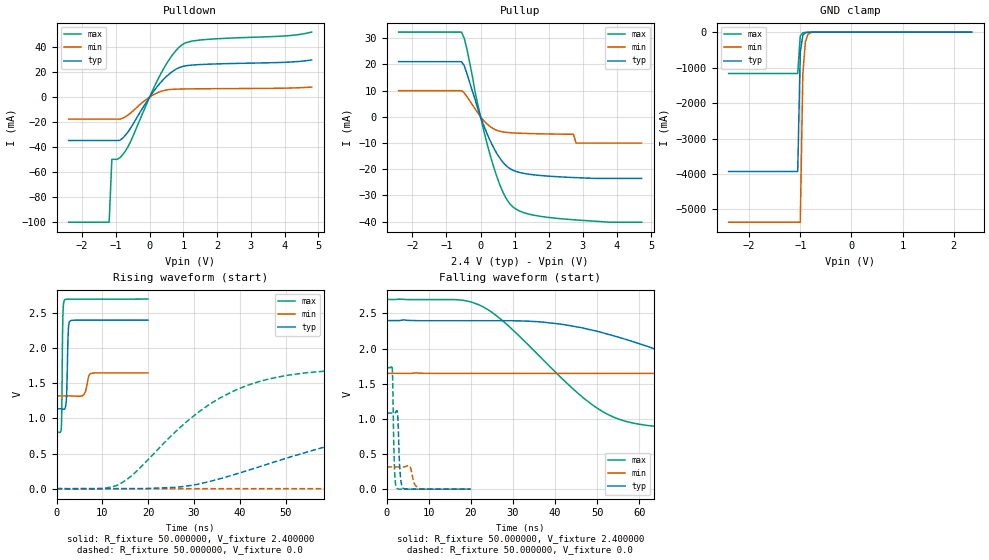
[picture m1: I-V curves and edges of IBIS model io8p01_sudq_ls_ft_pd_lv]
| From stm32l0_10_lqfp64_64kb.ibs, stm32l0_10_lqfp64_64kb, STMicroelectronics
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|   Model io8p01_sudq_ls_ft_pd_lv
[Model]  io8p01_sudq_ls_ft_pd_lv
Model_type I/O
Polarity   Non-Inverting
Enable   Active-Low
Vinl =   0.720000V
Vinh =   1.680000V
Vmeas =  1.200000V
Cref =   50.000000pF
Rref =   100.000000M
Vref =   0.0V
C_comp   2.317700pF   2.286600pF   2.332700pF
[Temperature Range]   25.000000   0.105000k   -40.000000
[Pullup Reference]   2.400000V   1.650000V   2.700000V
[Pulldown Reference]   0.0V   0.0V   0.0V
[POWER Clamp Reference]   2.400000V   1.650000V   2.700000V
[GND Clamp Reference]   0.0V   0.0V   0.0V
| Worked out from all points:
|   slope of the pulldown table from 0 to 0.36 V, typ, clamps not added: 28.4 ohm
|   slope of the pullup table from 0 to 0.36 V, typ, clamps not added: 32.2 ohm
|   GND clamp passes 1 mA (typ) near -0.64 V on its own axis
|   rising waveform, R_fixture 50.000000, V_fixture 2.400000: 20-80 % time 276ps typ, 630ps min, 184ps max; typ from 1.14 V to 2.4 V
|   rising waveform, R_fixture 50.000000, V_fixture 0.0: 20-80 % time 39.8ns typ, 107ns min, 19.5ns max; typ from 0 V to 1.08 V
|   falling waveform, R_fixture 50.000000, V_fixture 2.400000: 20-80 % time 41.2ns typ, 107ns min, 20.3ns max; typ from 2.4 V to 1.14 V
|   falling waveform, R_fixture 50.000000, V_fixture 0.0: 20-80 % time 453ps typ, 828ps min, 354ps max; typ from 1.08 V to 0 V
[Pulldown]
|Voltage   I(typ)   I(min)   I(max)
-2.4V     -34.71mA   -17.62mA   -100mA
-1.2V     -34.71mA   -17.62mA   -100mA
-1.12V    -34.71mA   -17.62mA   -49.77mA
-960mV    -34.71mA   -17.62mA   -49.77mA
-720mV    -30.52mA   -15.81mA   -43.23mA
-560mV    -24.66mA   -12.69mA   -35.3mA
-80mV     -3.3mA     -1.497mA   -4.982mA
320mV     11.47mA    4.39mA     18.08mA
640mV     19.72mA    6.139mA    32.34mA
960mV     24.33mA    6.432mA    41.77mA
1.52V     26.01mA    6.612mA    45.64mA
4.8V      29.64mA    7.944mA    51.92mA
[Pullup]
|Voltage   I(typ)   I(min)   I(max)
-2.4V     21.06mA    9.987mA    32.34mA
-560mV    21.06mA    9.987mA    32.34mA
-480mV    19.56mA    9.181mA    30.05mA
-400mV    16.53mA    7.734mA    25.89mA
-80mV     3.011mA    1.498mA    4.671mA
320mV     -10.16mA   -4.078mA   -16.34mA
640mV     -17.08mA   -5.718mA   -28.28mA
960mV     -20.45mA   -6.129mA   -34.5mA
2V        -22.64mA   -6.529mA   -38.4mA
2.72V     -23.16mA   -6.64mA    -39.27mA
2.8V      -23.2mA    -10mA      -39.35mA
4.72V     -23.5mA    -10mA      -40.2mA
[GND_clamp]
|Voltage   I(typ)   I(min)   I(max)
-2.4V     -3.929A    -5.359A    -1.166A
-1.05V    -3.929A    -5.359A    -1.166A
-1V       -574.5mA   -5.359A    -109.1mA
-950mV    -90.03mA   -1.192A    -18.56mA
-900mV    -18.42mA   -269.7mA   -9.058mA
-850mV    -6.777mA   -63.61mA   -6.588mA
-800mV    -4.039mA   -16.67mA   -4.867mA
-650mV    -1.055mA   -1.235mA   -1.154mA
2.35V     52.69uA    50.02uA    36.84uA
[POWER_clamp]
|Voltage   I(typ)   I(min)   I(max)
-2.4V     0A         0A         0A
0V        0A         0A         0A
[Ramp]
| variable   typ   min   max
dV/dt_r  0.65004/39.76015n   0.18950/0.10689u   1.03746/19.42297n
dV/dt_f  0.75708/41.15289n   0.19506/0.10670u   1.13772/20.24690n
R_load = 50.000000
[Rising Waveform]
R_fixture= 50.000000
V_fixture= 2.400000
V_fixture_min= 1.650000
V_fixture_max= 2.700000
|time   V(typ)   V(min)   V(max)
0s        1.137V     1.32V      803.3mV
1.041ns   1.137V     1.32V      870.1mV
1.161ns   1.136V     1.32V      1.186V
1.361ns   1.133V     1.32V      2.385V
1.722ns   1.132V     1.32V      2.685V
2.162ns   1.288V     1.32V      2.697V
2.563ns   2.246V     1.32V      2.697V
2.963ns   2.388V     1.32V      2.698V
7.608ns   2.399V     1.642V     2.698V
19.94ns   2.399V     1.649V     2.7V
[Rising Waveform]
R_fixture= 50.000000
V_fixture= 0.0
V_fixture_min= 0.0
V_fixture_max= 0.0
|time   V(typ)   V(min)   V(max)
0s        1.262nV    6.227nV    1.047nV
14.01ns   -220.5uV   -46.69uV   74.63mV
30.03ns   53.04mV    -46.12uV   1.041V
40.04ns   225.4mV    -45.81uV   1.43V
48.05ns   390.7mV    -38.86uV   1.586V
61.06ns   635.3mV    -10.19uV   1.687V
90.09ns   948mV      1.517mV    1.725V
134.1ns   1.067V     59.43mV    1.729V
256.3ns   1.083V     267mV      1.729V
498.5ns   1.083V     316.1mV    1.729V
[Falling Waveform]
R_fixture= 50.000000
V_fixture= 2.400000
V_fixture_min= 1.650000
V_fixture_max= 2.700000
|time   V(typ)   V(min)   V(max)
0s        2.399V     1.649V     2.7V
22.02ns   2.397V     1.648V     2.622V
37.04ns   2.377V     1.648V     1.849V
52.05ns   2.213V     1.648V     1.078V
59.06ns   2.088V     1.648V     934.2mV
73.07ns   1.798V     1.647V     852.8mV
100.1ns   1.36V      1.647V     815.1mV
138.1ns   1.198V     1.632V     805.1mV
292.3ns   1.138V     1.376V     803.3mV
498.5ns   1.137V     1.32V      803.3mV
[Falling Waveform]
R_fixture= 50.000000
V_fixture= 0.0
V_fixture_min= 0.0
V_fixture_max= 0.0
|time   V(typ)   V(min)   V(max)
0s        1.083V     316.1mV    1.729V
1.361ns   1.083V     316.1mV    1.718V
1.882ns   1.083V     316.1mV    318.6mV
2.442ns   1.117V     316.1mV    15.2mV
2.683ns   1.015V     316.1mV    3.975mV
3.203ns   248mV      315.9mV    146.4uV
3.844ns   17.68mV    315.6mV    -22.31uV
5.445ns   -798.8nV   330.6mV    -26.61uV
7.928ns   -5.539uV   7.752mV    -22.07uV
19.94ns   1.262nV    6.227nV    1.047nV
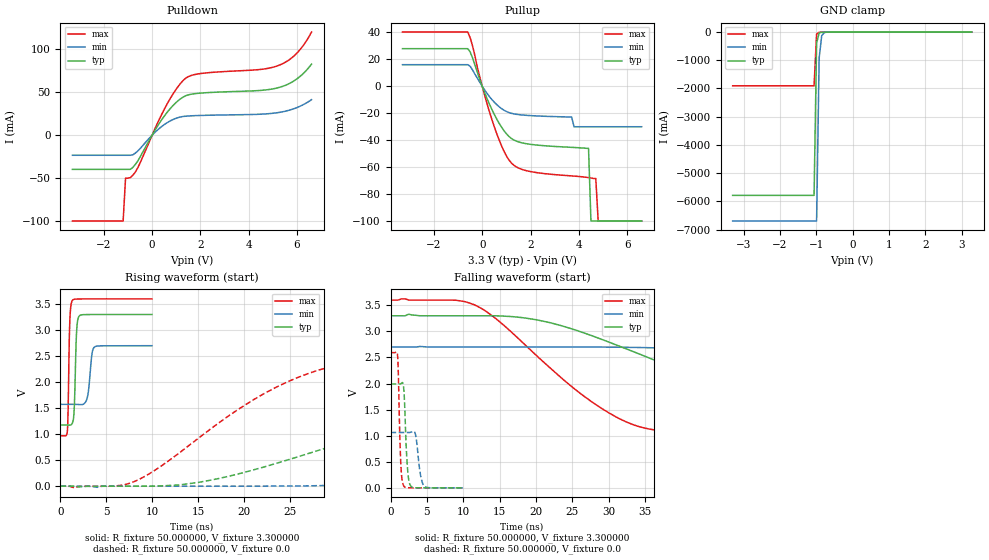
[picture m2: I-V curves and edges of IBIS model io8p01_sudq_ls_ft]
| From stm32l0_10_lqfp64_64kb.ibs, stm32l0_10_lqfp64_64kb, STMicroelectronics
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|   Model io8p01_sudq_ls_ft
[Model]  io8p01_sudq_ls_ft
Model_type I/O
Polarity   Non-Inverting
Enable   Active-Low
Vinl =   0.990000V
Vinh =   2.310000V
Vmeas =  1.650000V
Cref =   50.000000pF
Rref =   100.000000M
Vref =   0.0V
C_comp   2.343000pF   2.309800pF   2.393900pF
[Temperature Range]   25.000000   0.125000k   -40.000000
[Pullup Reference]   3.300000V   2.700000V   3.600000V
[Pulldown Reference]   0.0V   0.0V   0.0V
[POWER Clamp Reference]   3.300000V   2.700000V   3.600000V
[GND Clamp Reference]   0.0V   0.0V   0.0V
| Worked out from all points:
|   slope of the pulldown table from 0 to 0.495 V, typ, clamps not added: 22.6 ohm
|   slope of the pullup table from 0 to 0.495 V, typ, clamps not added: 23.9 ohm
|   GND clamp passes 1 mA (typ) near -0.64 V on its own axis
|   rising waveform, R_fixture 50.000000, V_fixture 3.300000: 20-80 % time 208ps typ, 361ps min, 164ps max; typ from 1.18 V to 3.3 V
|   rising waveform, R_fixture 50.000000, V_fixture 0.0: 20-80 % time 27.1ns typ, 59.7ns min, 13.6ns max; typ from 0 V to 1.99 V
|   falling waveform, R_fixture 50.000000, V_fixture 3.300000: 20-80 % time 24.4ns typ, 53.6ns min, 13.4ns max; typ from 3.3 V to 1.18 V
|   falling waveform, R_fixture 50.000000, V_fixture 0.0: 20-80 % time 381ps typ, 552ps min, 301ps max; typ from 1.99 V to 0 V
[Pulldown]
|Voltage   I(typ)   I(min)   I(max)
-3.3V     -39.8mA    -23.37mA   -100mA
-1.2V     -39.8mA    -23.37mA   -100mA
-1.1V     -39.8mA    -23.37mA   -50.1mA
-900mV    -39.8mA    -23.37mA   -49.43mA
-700mV    -34.25mA   -21mA      -43.13mA
600mV     25.84mA    14.18mA    35.34mA
1V        38.32mA    19.82mA    53.81mA
1.4V      46.09mA    22.19mA    66.63mA
2V        49.05mA    23.02mA    71.83mA
5.2V      55.23mA    26.32mA    80.92mA
6V        65.76mA    32.26mA    95.84mA
6.6V      82.81mA    41.43mA    120.2mA
[Pullup]
|Voltage   I(typ)   I(min)   I(max)
-3.3V     27.97mA    16.08mA    40.34mA
-600mV    27.97mA    16.08mA    40.34mA
400mV     -17.21mA   -9.813mA   -24.69mA
800mV     -30.32mA   -16.54mA   -44.19mA
1.2V      -38.62mA   -20mA      -56.79mA
3.7V      -45.29mA   -22.8mA    -66.5mA
3.8V      -45.39mA   -30mA      -66.64mA
4.4V      -46mA      -30mA      -67.77mA
4.5V      -100mA     -30mA      -68.06mA
4.7V      -100mA     -30mA      -68.4mA
4.8V      -100mA     -30mA      -100mA
6.6V      -100mA     -30mA      -100mA
[GND_clamp]
|Voltage   I(typ)   I(min)   I(max)
-3.3V     -5.787A    -6.696A    -1.906A
-1.06V    -5.787A    -6.696A    -1.906A
-990mV    -393.4mA   -6.696A    -70.75mA
-920mV    -33.02mA   -919.4mA   -10.9mA
-850mV    -6.829mA   -131.3mA   -6.521mA
-780mV    -3.478mA   -21.06mA   -4.208mA
3.28V     0A         0A         0A
[POWER_clamp]
|Voltage   I(typ)   I(min)   I(max)
-3.28V    0A         0A         0A
0V        0A         0A         0A
[Ramp]
| variable   typ   min   max
dV/dt_r  1.19496/27.09964n   0.63558/59.72123n   1.55568/13.61585n
dV/dt_f  1.27398/24.40861n   0.67062/53.57510n   1.57788/13.41077n
R_load = 50.000000
[Rising Waveform]
R_fixture= 50.000000
V_fixture= 3.300000
V_fixture_min= 2.700000
V_fixture_max= 3.600000
|time   V(typ)   V(min)   V(max)
0s        1.177V     1.573V     970.2mV
760.8ps   1.176V     1.573V     1.077V
1.021ns   1.173V     1.573V     3.169V
1.301ns   1.213V     1.573V     3.569V
1.502ns   1.496V     1.573V     3.592V
1.782ns   3.03V      1.572V     3.597V
2.042ns   3.269V     1.569V     3.598V
2.923ns   3.298V     1.701V     3.599V
3.684ns   3.299V     2.671V     3.6V
9.97ns    3.3V       2.7V       3.6V
[Rising Waveform]
R_fixture= 50.000000
V_fixture= 0.0
V_fixture_min= 0.0
V_fixture_max= 0.0
|time   V(typ)   V(min)   V(max)
0s        -353.2nV   -2.197uV   -101.6nV
8.008ns   -456.3uV   -169.7uV   85.68mV
15.02ns   72.53mV    -164.6uV   918.9mV
25.03ns   518.6mV    3.999mV    2.027V
31.53ns   874.7mV    26.04mV    2.378V
39.04ns   1.23V      72.54mV    2.52V
57.56ns   1.752V     276.6mV    2.584V
81.08ns   1.943V     577.2mV    2.592V
138.1ns   1.991V     965.7mV    2.593V
249.2ns   1.992V     1.062V     2.593V
[Falling Waveform]
R_fixture= 50.000000
V_fixture= 3.300000
V_fixture_min= 2.700000
V_fixture_max= 3.600000
|time   V(typ)   V(min)   V(max)
0s        3.3V       2.7V       3.6V
11.51ns   3.3V       2.7V       3.512V
20.02ns   3.224V     2.7V       2.544V
29.03ns   2.849V     2.699V     1.525V
34.03ns   2.578V     2.692V     1.181V
39.54ns   2.268V     2.67V      1.059V
57.06ns   1.471V     2.519V     987.8mV
76.58ns   1.263V     2.253V     974.6mV
135.6ns   1.183V     1.696V     970.3mV
249.2ns   1.177V     1.573V     970.2mV
[Falling Waveform]
R_fixture= 50.000000
V_fixture= 0.0
V_fixture_min= 0.0
V_fixture_max= 0.0
|time   V(typ)   V(min)   V(max)
0s        1.992V     1.062V     2.593V
961ps     1.992V     1.062V     2.539V
1.401ns   1.996V     1.062V     480.8mV
1.802ns   1.915V     1.062V     39.14mV
2.302ns   424.6mV    1.061V     2.843mV
2.763ns   38.03mV    1.065V     945.4uV
3.423ns   1.815mV    1.024V     599.2uV
4.104ns   543.8uV    260.9mV    390.7uV
4.665ns   343uV      28.71mV    271.5uV
9.97ns    -353.2nV   -2.197uV   -101.6nV
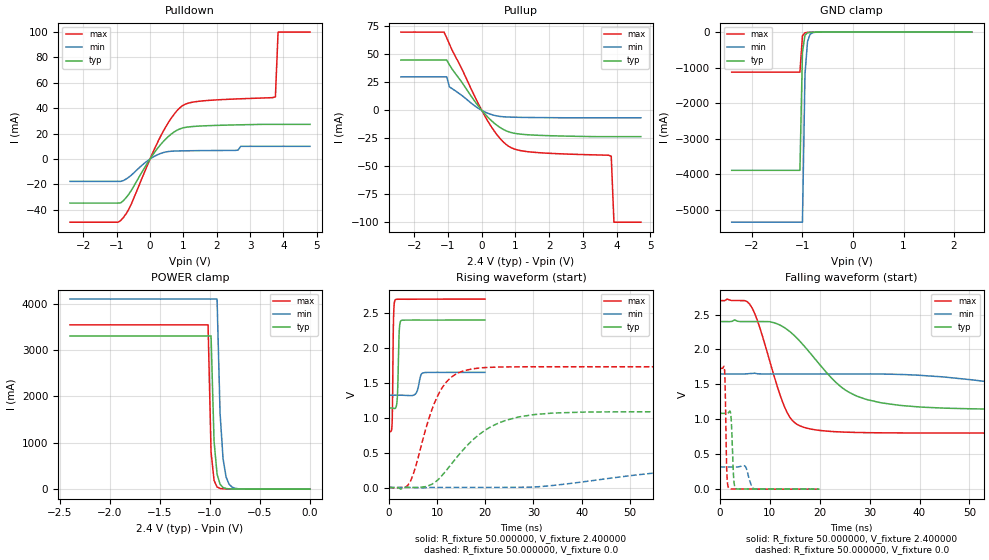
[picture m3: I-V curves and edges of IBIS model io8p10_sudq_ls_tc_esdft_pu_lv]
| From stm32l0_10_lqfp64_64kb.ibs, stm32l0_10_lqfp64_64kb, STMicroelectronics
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|   Model io8p10_sudq_ls_tc_esdft_pu_lv
[Model]  io8p10_sudq_ls_tc_esdft_pu_lv
Model_type I/O
Polarity   Non-Inverting
Enable   Active-Low
Vinl =   0.720000V
Vinh =   1.680000V
Vmeas =  1.200000V
Cref =   50.000000pF
Rref =   100.000000M
Vref =   0.0V
C_comp   2.242700pF   2.201100pF   2.288600pF
[Temperature Range]   25.000000   0.105000k   -40.000000
[Pullup Reference]   2.400000V   1.650000V   2.700000V
[Pulldown Reference]   0.0V   0.0V   0.0V
[POWER Clamp Reference]   2.400000V   1.650000V   2.700000V
[GND Clamp Reference]   0.0V   0.0V   0.0V
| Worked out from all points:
|   slope of the pulldown table from 0 to 0.36 V, typ, clamps not added: 28.4 ohm
|   slope of the pullup table from 0 to 0.36 V, typ, clamps not added: 32.2 ohm
|   GND clamp passes 1 mA (typ) near -0.65 V on its own axis
|   POWER clamp passes 1 mA (typ) near -0.63 V on its own axis
|   rising waveform, R_fixture 50.000000, V_fixture 2.400000: 20-80 % time 280ps typ, 635ps min, 186ps max; typ from 1.14 V to 2.4 V
|   rising waveform, R_fixture 50.000000, V_fixture 0.0: 20-80 % time 9.54ns typ, 25.3ns min, 4.93ns max; typ from 0.001 V to 1.09 V
|   falling waveform, R_fixture 50.000000, V_fixture 2.400000: 20-80 % time 10.1ns typ, 27.2ns min, 4.96ns max; typ from 2.4 V to 1.14 V
|   falling waveform, R_fixture 50.000000, V_fixture 0.0: 20-80 % time 356ps typ, 760ps min, 262ps max; typ from 1.09 V to 0.001 V
[Pulldown]
|Voltage   I(typ)   I(min)   I(max)
-2.4V     -34.71mA   -17.61mA   -49.77mA
-880mV    -34.55mA   -17.61mA   -48.41mA
-560mV    -24.66mA   -12.69mA   -35.31mA
240mV     8.893mA    3.542mA    13.9mA
560mV     17.98mA    5.931mA    29.16mA
880mV     23.58mA    6.388mA    40.03mA
1.44V     25.89mA    6.593mA    45.41mA
2.64V     26.92mA    7mA        47.38mA
2.72V     26.96mA    10mA       47.46mA
3.76V     27.3mA     10mA       49mA
3.84V     27.3mA     10mA       100mA
4.8V      27.3mA     10mA       100mA
[Pullup]
|Voltage   I(typ)   I(min)   I(max)
-2.4V     45mA       30mA       70mA
-1.12V    45mA       30mA       70mA
-1.04V    45mA       30mA       64.8mA
-960mV    40.7mA     21mA       59.3mA
80mV      -2.838mA   -1.261mA   -4.478mA
480mV     -14.04mA   -5.167mA   -22.91mA
800mV     -19.2mA    -5.978mA   -32.18mA
1.04V     -20.85mA   -6.184mA   -35.23mA
1.44V     -21.93mA   -6.373mA   -37.19mA
3.84V     -23.5mA    -6.63mA    -41mA
3.92V     -23.5mA    -6.63mA    -100mA
4.72V     -23.5mA    -6.63mA    -100mA
[GND_clamp]
|Voltage   I(typ)   I(min)   I(max)
-2.4V     -3.892A    -5.353A    -1.127A
-1.05V    -3.892A    -5.353A    -1.127A
-1V       -568.8mA   -5.353A    -105.4mA
-950mV    -88.95mA   -1.19A     -18.03mA
-900mV    -18.15mA   -269.2mA   -8.959mA
-850mV    -6.699mA   -63.45mA   -6.568mA
-800mV    -4.014mA   -16.61mA   -4.858mA
-650mV    -1.043mA   -1.218mA   -1.146mA
2.35V     0A         0A         0A
[POWER_clamp]
|Voltage   I(typ)   I(min)   I(max)
-2.4V     3.303A     4.097A     3.542A
-1.02V    3.303A     4.097A     3.542A
-990mV    3.303A     4.097A     802.4mA
-960mV    1.032A     4.097A     186.5mA
-930mV    325.2mA    4.097A     47.6mA
-900mV    104.9mA    1.637A     15.79mA
-870mV    35.84mA    655.7mA    8.024mA
-840mV    13.94mA    263.9mA    5.676mA
-810mV    6.724mA    107.2mA    4.568mA
-780mV    4.1mA      44.41mA    3.772mA
-690mV    1.753mA    4.377mA    1.918mA
0V        0A         0A         0A
[Ramp]
| variable   typ   min   max
dV/dt_r  0.65094/9.53348n   0.19037/25.24837n   1.03799/4.90972n
dV/dt_f  0.75624/10.10593n   0.19656/27.16818n   1.13750/4.95624n
R_load = 50.000000
[Rising Waveform]
R_fixture= 50.000000
V_fixture= 2.400000
V_fixture_min= 1.650000
V_fixture_max= 2.700000
|time   V(typ)   V(min)   V(max)
0s        1.14V      1.322V     804mV
680.7ps   1.139V     1.322V     930.2mV
961ps     1.135V     1.322V     2.4V
1.321ns   1.135V     1.322V     2.689V
1.722ns   1.257V     1.323V     2.697V
2.162ns   2.251V     1.323V     2.697V
2.563ns   2.393V     1.323V     2.698V
5.485ns   2.399V     1.339V     2.698V
7.167ns   2.399V     1.643V     2.699V
19.94ns   2.4V       1.65V      2.7V
[Rising Waveform]
R_fixture= 50.000000
V_fixture= 0.0
V_fixture_min= 0.0
V_fixture_max= 0.0
|time   V(typ)   V(min)   V(max)
0s        906uV      1.335mV    515.9uV
4.505ns   2.02mV     1.434mV    94.9mV
9.009ns   50.56mV    2.375mV    1.131V
11.51ns   212.2mV    2.379mV    1.476V
14.51ns   468.8mV    2.376mV    1.646V
19.52ns   799.9mV    2.418mV    1.717V
27.03ns   1.013V     3.91mV     1.729V
41.04ns   1.082V     88.92mV    1.73V
89.59ns   1.086V     310.1mV    1.73V
249.2ns   1.086V     318.6mV    1.73V
[Falling Waveform]
R_fixture= 50.000000
V_fixture= 2.400000
V_fixture_min= 1.650000
V_fixture_max= 2.700000
|time   V(typ)   V(min)   V(max)
0s        2.4V       1.65V      2.7V
6.006ns   2.4V       1.656V     2.649V
13.51ns   2.285V     1.65V      1.095V
15.52ns   2.158V     1.65V      927.2mV
20.02ns   1.784V     1.65V      841.2mV
24.52ns   1.452V     1.65V      818.5mV
29.03ns   1.293V     1.65V      810.1mV
45.05ns   1.16V      1.605V     804.3mV
96.1ns    1.14V      1.343V     804mV
249.2ns   1.14V      1.322V     804mV
[Falling Waveform]
R_fixture= 50.000000
V_fixture= 0.0
V_fixture_min= 0.0
V_fixture_max= 0.0
|time   V(typ)   V(min)   V(max)
0s        1.086V     318.6mV    1.73V
961ps     1.086V     318.6mV    1.72V
1.121ns   1.086V     318.6mV    1.37V
1.401ns   1.085V     318.6mV    288.9mV
1.802ns   1.098V     318.6mV    16.52mV
2.242ns   1.055V     318.6mV    3.592mV
2.803ns   153.9mV    318.4mV    3.122mV
3.243ns   10.07mV    318.1mV    3.142mV
6.887ns   2.801mV    6.977mV    2.777mV
19.94ns   906uV      1.335mV    515.9uV
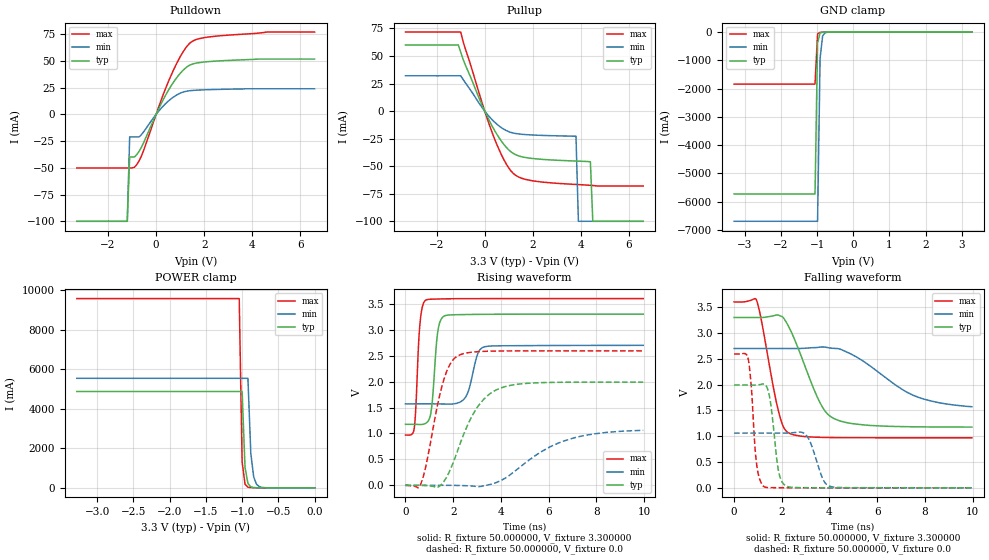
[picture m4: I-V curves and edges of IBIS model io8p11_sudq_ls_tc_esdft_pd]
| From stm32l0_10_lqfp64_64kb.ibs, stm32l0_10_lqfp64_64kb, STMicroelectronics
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|   Model io8p11_sudq_ls_tc_esdft_pd
[Model]  io8p11_sudq_ls_tc_esdft_pd
Model_type I/O
Polarity   Non-Inverting
Enable   Active-Low
Vinl =   0.990000V
Vinh =   2.310000V
Vmeas =  1.650000V
Cref =   50.000000pF
Rref =   100.000000M
Vref =   0.0V
C_comp   2.248300pF   2.207300pF   2.311900pF
[Temperature Range]   25.000000   0.125000k   -40.000000
[Pullup Reference]   3.300000V   2.700000V   3.600000V
[Pulldown Reference]   0.0V   0.0V   0.0V
[POWER Clamp Reference]   3.300000V   2.700000V   3.600000V
[GND Clamp Reference]   0.0V   0.0V   0.0V
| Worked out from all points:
|   slope of the pulldown table from 0 to 0.495 V, typ, clamps not added: 22.6 ohm
|   slope of the pullup table from 0 to 0.495 V, typ, clamps not added: 23.9 ohm
|   GND clamp passes 1 mA (typ) near -0.64 V on its own axis
|   POWER clamp passes 1 mA (typ) near -0.63 V on its own axis
|   rising waveform, R_fixture 50.000000, V_fixture 3.300000: 20-80 % time 210ps typ, 364ps min, 166ps max; typ from 1.18 V to 3.3 V
|   rising waveform, R_fixture 50.000000, V_fixture 0.0: 20-80 % time 1.19ns typ, 2.19ns min, 713ps max; typ from 0 V to 1.99 V
|   falling waveform, R_fixture 50.000000, V_fixture 3.300000: 20-80 % time 1.12ns typ, 2.15ns min, 643ps max; typ from 3.3 V to 1.18 V
|   falling waveform, R_fixture 50.000000, V_fixture 0.0: 20-80 % time 291ps typ, 460ps min, 230ps max; typ from 1.99 V to 0 V
[Pulldown]
|Voltage   I(typ)   I(min)   I(max)
-3.3V     -100mA     -100mA     -50.11mA
-1.2V     -100mA     -100mA     -50.11mA
-1.1V     -39.8mA    -21mA      -50.11mA
-900mV    -39.8mA    -21mA      -49.43mA
-600mV    -30.26mA   -18.59mA   -38.38mA
500mV     22.11mA    12.28mA    30.06mA
900mV     35.58mA    18.71mA    49.62mA
1.3V      44.74mA    21.88mA    64.23mA
1.7V      48.13mA    22.72mA    70.3mA
2.4V      49.79mA    23.3mA     73.03mA
4.6V      51.8mA     24mA       77.1mA
6.6V      51.8mA     24mA       77.1mA
[Pullup]
|Voltage   I(typ)   I(min)   I(max)
-3.3V     60mA       32mA       71.7mA
-1.1V     60mA       32mA       71.7mA
-1V       53.5mA     32mA       71.7mA
-100mV    4.893mA    2.926mA    6.861mA
400mV     -17.21mA   -9.813mA   -24.69mA
900mV     -32.92mA   -17.72mA   -48.15mA
1.3V      -39.75mA   -20.41mA   -58.47mA
3.8V      -45.36mA   -22.8mA    -66.6mA
3.9V      -45.44mA   -100mA     -66.72mA
4.4V      -46mA      -100mA     -67.4mA
4.5V      -100mA     -100mA     -67.56mA
6.6V      -100mA     -100mA     -68mA
[GND_clamp]
|Voltage   I(typ)   I(min)   I(max)
-3.3V     -5.732A    -6.7A      -1.842A
-1.06V    -5.732A    -6.7A      -1.842A
-990mV    -389.4mA   -6.7A      -68.35mA
-920mV    -32.58mA   -928mA     -10.73mA
-850mV    -6.776mA   -138mA     -6.518mA
-780mV    -3.484mA   -24.13mA   -4.216mA
-570mV    -313uA     -578.6uA   -266.4uA
3.28V     74.9uA     89.13uA    52.44uA
[POWER_clamp]
|Voltage   I(typ)   I(min)   I(max)
-3.28V    4.87A      5.538A     9.569A
-1.04V    4.87A      5.538A     9.569A
-1V       4.87A      5.538A     1.315A
-960mV    1.032A     5.538A     186.5mA
-920mV    222.2mA    5.538A     31.64mA
-880mV    50.73mA    1.734A     9.582mA
-840mV    13.93mA    544.8mA    5.668mA
-800mV    5.556mA    172.7mA    4.276mA
-760mV    3.231mA    55.84mA    3.297mA
-680mV    1.597mA    6.983mA    1.741mA
0V        0A         0A         0A
[Ramp]
| variable   typ   min   max
dV/dt_r  1.19376/1.19239n   0.60642/2.06103n   1.55514/0.71155n
dV/dt_f  1.27194/1.12153n   0.59340/1.93500n   1.57757/0.64185n
R_load = 50.000000
[Rising Waveform]
R_fixture= 50.000000
V_fixture= 3.300000
V_fixture_min= 2.700000
V_fixture_max= 3.600000
|time   V(typ)   V(min)   V(max)
0s        1.176V     1.571V     969.1mV
360.4ps   1.175V     1.571V     1.08V
600.6ps   1.173V     1.571V     3.079V
860.9ps   1.199V     1.571V     3.572V
1.081ns   1.442V     1.571V     3.588V
1.381ns   3.032V     1.569V     3.592V
1.642ns   3.267V     1.567V     3.595V
2.523ns   3.292V     1.702V     3.599V
3.283ns   3.296V     2.666V     3.599V
9.97ns    3.299V     2.698V     3.599V
[Rising Waveform]
R_fixture= 50.000000
V_fixture= 0.0
V_fixture_min= 0.0
V_fixture_max= 0.0
|time   V(typ)   V(min)   V(max)
0s        -1.611uV   12.67uV    -132.9uV
640.6ps   -938.1uV   -6.181uV   24.99mV
840.8ps   -5.316mV   6.648uV    341.3mV
1.582ns   57.96mV    175.9uV    1.994V
1.882ns   304.7mV    -458.6uV   2.344V
2.202ns   687.8mV    -2.877mV   2.497V
3.063ns   1.537V     -25.78mV   2.578V
4.024ns   1.881V     96.97mV    2.59V
6.627ns   1.987V     851.8mV    2.592V
9.97ns    1.99V      1.06V      2.592V
[Falling Waveform]
R_fixture= 50.000000
V_fixture= 3.300000
V_fixture_min= 2.700000
V_fixture_max= 3.600000
|time   V(typ)   V(min)   V(max)
0s        3.299V     2.698V     3.599V
940.9ps   3.299V     2.698V     3.634V
1.862ns   3.345V     2.698V     1.484V
2.062ns   3.297V     2.698V     1.187V
2.282ns   3.128V     2.698V     1.065V
3.544ns   1.703V     2.722V     978.8mV
4.104ns   1.363V     2.703V     973.5mV
5.105ns   1.235V     2.542V     970.4mV
7.528ns   1.182V     1.789V     969.2mV
9.97ns    1.176V     1.571V     969.1mV
[Falling Waveform]
R_fixture= 50.000000
V_fixture= 0.0
V_fixture_min= 0.0
V_fixture_max= 0.0
|time   V(typ)   V(min)   V(max)
0s        1.99V      1.06V      2.592V
600.6ps   1.99V      1.06V      2.475V
940.9ps   1.991V     1.06V      470.2mV
1.261ns   2.007V     1.06V      21.31mV
1.502ns   1.726V     1.06V      3.791mV
1.882ns   285.4mV    1.06V      2.39mV
2.202ns   32.27mV    1.06V      1.817mV
3.043ns   2.761mV    1.01V      751.3uV
4.084ns   1.369mV    20.88mV    137.8uV
9.97ns    -1.611uV   12.67uV    -132.9uV
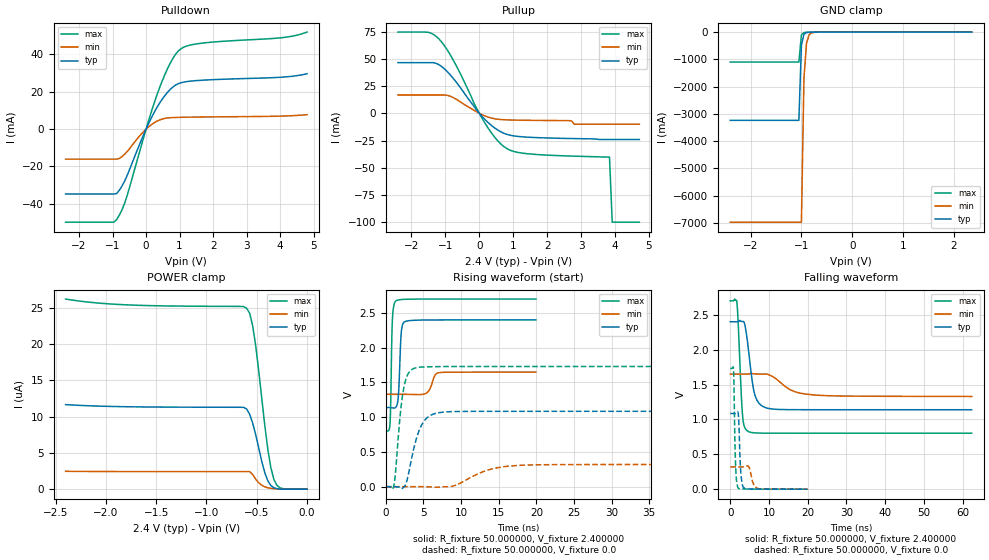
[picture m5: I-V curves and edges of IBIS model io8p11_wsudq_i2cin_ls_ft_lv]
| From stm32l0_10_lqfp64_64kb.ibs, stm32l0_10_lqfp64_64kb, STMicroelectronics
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|   Model io8p11_wsudq_i2cin_ls_ft_lv
[Model]  io8p11_wsudq_i2cin_ls_ft_lv
Model_type I/O
Polarity   Non-Inverting
Enable   Active-Low
Vinl =   0.720000V
Vinh =   1.680000V
Vmeas =  1.200000V
Cref =   50.000000pF
Rref =   100.000000M
Vref =   0.0V
C_comp   2.943600pF   2.939200pF   2.965100pF
[Temperature Range]   25.000000   0.125000k   -40.000000
[Pullup Reference]   2.400000V   1.650000V   2.700000V
[Pulldown Reference]   0.0V   0.0V   0.0V
[POWER Clamp Reference]   2.400000V   1.650000V   2.700000V
[GND Clamp Reference]   0.0V   0.0V   0.0V
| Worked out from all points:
|   slope of the pulldown table from 0 to 0.36 V, typ, clamps not added: 28.5 ohm
|   slope of the pullup table from 0 to 0.36 V, typ, clamps not added: 32.2 ohm
|   GND clamp passes 1 mA (typ) near -0.65 V on its own axis
|   rising waveform, R_fixture 50.000000, V_fixture 2.400000: 20-80 % time 288ps typ, 666ps min, 197ps max; typ from 1.14 V to 2.4 V
|   rising waveform, R_fixture 50.000000, V_fixture 0.0: 20-80 % time 1.59ns typ, 3.97ns min, 931ps max; typ from 0 V to 1.08 V
|   falling waveform, R_fixture 50.000000, V_fixture 2.400000: 20-80 % time 1.81ns typ, 5.2ns min, 921ps max; typ from 2.4 V to 1.14 V
|   falling waveform, R_fixture 50.000000, V_fixture 0.0: 20-80 % time 491ps typ, 912ps min, 386ps max; typ from 1.08 V to 0 V
[Pulldown]
|Voltage   I(typ)   I(min)   I(max)
-2.4V     -34.71mA   -16.06mA   -49.82mA
-960mV    -34.71mA   -16.06mA   -49.82mA
-880mV    -34.55mA   -16.06mA   -48.46mA
-720mV    -30.53mA   -14.74mA   -43.27mA
-560mV    -24.65mA   -11.94mA   -35.33mA
0V        225fA      0A         140fA
400mV     13.84mA    4.882mA    22.03mA
720mV     21.25mA    6.107mA    35.26mA
1.04V     24.82mA    6.324mA    43.03mA
1.6V      26.11mA    6.486mA    45.88mA
4V        27.76mA    6.965mA    48.87mA
4.8V      29.64mA    7.736mA    51.96mA
[Pullup]
|Voltage   I(typ)   I(min)   I(max)
-2.4V     46.57mA    16.84mA    74.62mA
-1.52V    46.57mA    16.84mA    74.5mA
-1.2V     44.83mA    16.84mA    68.61mA
-720mV    30.24mA    13.64mA    46.11mA
-160mV    6.586mA    2.887mA    9.467mA
160mV     -5.477mA   -2.317mA   -8.695mA
480mV     -14.04mA   -5.139mA   -22.91mA
800mV     -19.2mA    -6.004mA   -32.18mA
1.52V     -22.07mA   -6.444mA   -37.42mA
3.84V     -24mA      -10mA      -40.2mA
3.92V     -24mA      -10mA      -100mA
4.72V     -24mA      -10mA      -100mA
[GND_clamp]
|Voltage   I(typ)   I(min)   I(max)
-2.4V     -3.237A    -6.973A    -1.1A
-1.05V    -3.237A    -6.973A    -1.1A
-1V       -475.8mA   -6.973A    -104.2mA
-950mV    -76.24mA   -1.682A    -18.39mA
-900mV    -16.61mA   -411.8mA   -9.105mA
-850mV    -6.547mA   -103.8mA   -6.589mA
-800mV    -3.998mA   -27.95mA   -4.86mA
-600mV    -514.5uA   -815.4uA   -496.5uA
2.35V     0A         0A         0A
[POWER_clamp]
|Voltage   I(typ)   I(min)   I(max)
-2.4V     11.64uA    2.459uA    26.17uA
-1.86V    11.37uA    2.424uA    25.42uA
-600mV    11.04uA    2.415uA    24.9uA
-570mV    10.3uA     2.415uA    24.21uA
-540mV    9.097uA    2.017uA    22.48uA
-510mV    7.497uA    1.362uA    19.73uA
-450mV    3.845uA    540.7nA    12.52uA
-390mV    1.154uA    197.9nA    5.528uA
-360mV    508.2nA    119.9nA    2.997uA
-330mV    204.4nA    72.97nA    1.375uA
-270mV    0A         0A         194.9nA
0V        0A         0A         0A
[Ramp]
| variable   typ   min   max
dV/dt_r  0.65070/1.58769n   0.19118/3.96914n   1.03800/0.92704n
dV/dt_f  0.75690/1.81226n   0.18906/5.18158n   1.13815/0.91860n
R_load = 50.000000
[Rising Waveform]
R_fixture= 50.000000
V_fixture= 2.400000
V_fixture_min= 1.650000
V_fixture_max= 2.700000
|time   V(typ)   V(min)   V(max)
0s        1.139V     1.329V     802mV
560.6ps   1.138V     1.329V     917.4mV
880.9ps   1.134V     1.329V     2.427V
1.321ns   1.142V     1.329V     2.672V
1.682ns   1.337V     1.329V     2.688V
2.082ns   2.254V     1.329V     2.693V
2.482ns   2.372V     1.329V     2.696V
5.405ns   2.399V     1.348V     2.7V
7.007ns   2.4V       1.639V     2.7V
19.94ns   2.4V       1.65V      2.7V
[Rising Waveform]
R_fixture= 50.000000
V_fixture= 0.0
V_fixture_min= 0.0
V_fixture_max= 0.0
|time   V(typ)   V(min)   V(max)
0s        -2.844uV   4.474uV    224.1uV
1.001ns   111.2uV    1.107uV    -13.28mV
1.251ns   -696.3uV   -1.743uV   168.1mV
2.002ns   -17.05mV   -4.393uV   1.132V
2.377ns   -8.152mV   10.56uV    1.419V
4.004ns   670.7mV    83.85uV    1.711V
5.38ns    981.7mV    -1.576mV   1.724V
7.883ns   1.075V     -707.1uV   1.729V
17.64ns   1.084V     306.5mV    1.73V
62.31ns   1.085V     318.6mV    1.73V
[Falling Waveform]
R_fixture= 50.000000
V_fixture= 2.400000
V_fixture_min= 1.650000
V_fixture_max= 2.700000
|time   V(typ)   V(min)   V(max)
0s        2.4V       1.65V      2.7V
1.752ns   2.4V       1.65V      2.656V
3.128ns   2.404V     1.65V      1.088V
3.754ns   2.357V     1.65V      881.6mV
4.63ns    2.028V     1.651V     828.4mV
5.631ns   1.563V     1.658V     811.5mV
6.381ns   1.347V     1.652V     806.9mV
9.384ns   1.164V     1.65V      802.7mV
19.52ns   1.139V     1.363V     802.1mV
62.31ns   1.139V     1.329V     802mV
[Falling Waveform]
R_fixture= 50.000000
V_fixture= 0.0
V_fixture_min= 0.0
V_fixture_max= 0.0
|time   V(typ)   V(min)   V(max)
0s        1.085V     318.6mV    1.73V
840.8ps   1.085V     318.6mV    1.71V
961ps     1.084V     318.6mV    1.483V
1.201ns   1.084V     318.6mV    685.2mV
1.401ns   1.084V     318.6mV    313.9mV
2.042ns   1.09V      318.6mV    17mV
2.683ns   273.5mV    318.3mV    4.117mV
3.403ns   25.32mV    319.9mV    2.316mV
7.207ns   764.7uV    7.861mV    453.3uV
19.94ns   -2.844uV   4.474uV    224.1uV
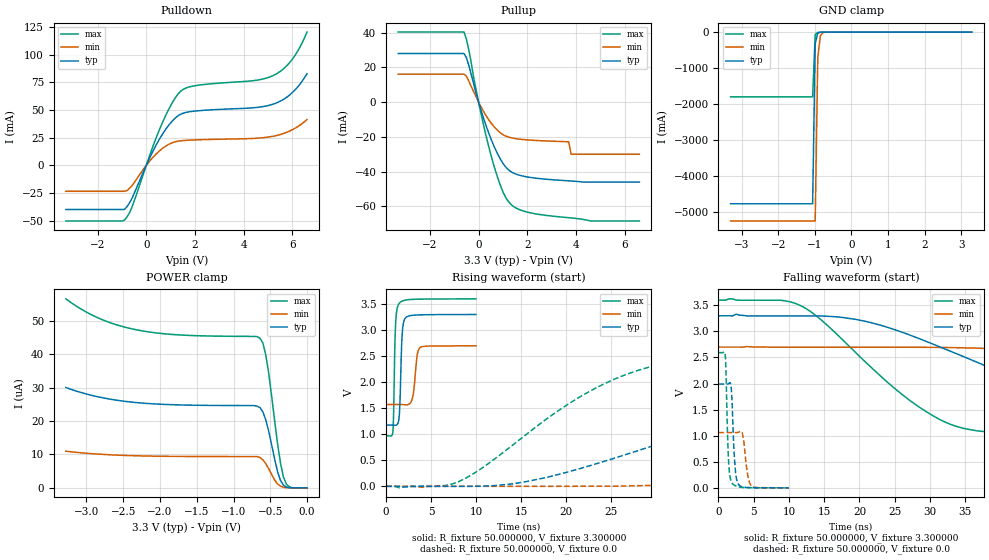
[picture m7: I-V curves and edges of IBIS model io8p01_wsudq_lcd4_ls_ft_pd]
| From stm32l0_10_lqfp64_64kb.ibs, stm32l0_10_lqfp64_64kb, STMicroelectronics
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|   Model io8p01_wsudq_lcd4_ls_ft_pd
[Model]  io8p01_wsudq_lcd4_ls_ft_pd
Model_type I/O
Polarity   Non-Inverting
Enable   Active-Low
Vinl =   0.990000V
Vinh =   2.310000V
Vmeas =  1.650000V
Cref =   50.000000pF
Rref =   100.000000M
Vref =   0.0V
C_comp   3.263700pF   3.224700pF   3.309000pF
[Temperature Range]   25.000000   0.125000k   -40.000000
[Pullup Reference]   3.300000V   2.700000V   3.600000V
[Pulldown Reference]   0.0V   0.0V   0.0V
[POWER Clamp Reference]   3.300000V   2.700000V   3.600000V
[GND Clamp Reference]   0.0V   0.0V   0.0V
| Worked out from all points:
|   slope of the pulldown table from 0 to 0.495 V, typ, clamps not added: 22.6 ohm
|   slope of the pullup table from 0 to 0.495 V, typ, clamps not added: 23.9 ohm
|   GND clamp passes 1 mA (typ) near -0.64 V on its own axis
|   rising waveform, R_fixture 50.000000, V_fixture 3.300000: 20-80 % time 236ps typ, 377ps min, 200ps max; typ from 1.18 V to 3.3 V
|   rising waveform, R_fixture 50.000000, V_fixture 0.0: 20-80 % time 27ns typ, 59.6ns min, 13.6ns max; typ from 0 V to 1.99 V
|   falling waveform, R_fixture 50.000000, V_fixture 3.300000: 20-80 % time 24.2ns typ, 53.5ns min, 13.3ns max; typ from 3.3 V to 1.18 V
|   falling waveform, R_fixture 50.000000, V_fixture 0.0: 20-80 % time 413ps typ, 576ps min, 337ps max; typ from 1.99 V to 0 V
[Pulldown]
|Voltage   I(typ)   I(min)   I(max)
-3.3V     -39.83mA   -23.37mA   -50.2mA
-900mV    -39.83mA   -23.37mA   -49.53mA
-600mV    -30.28mA   -18.59mA   -38.45mA
500mV     22.11mA    12.28mA    30.1mA
1V        38.33mA    19.81mA    53.88mA
1.4V      46.1mA     22.18mA    66.72mA
2V        49.07mA    23.02mA    71.93mA
4.4V      52.05mA    24.38mA    76.53mA
5.2V      55.25mA    26.3mA     81.02mA
5.6V      59.18mA    28.57mA    86.57mA
6V        65.79mA    32.24mA    95.97mA
6.6V      82.83mA    41.41mA    120.4mA
[Pullup]
|Voltage   I(typ)   I(min)   I(max)
-3.3V     27.97mA    16.08mA    40.33mA
-600mV    27.97mA    16.08mA    40.33mA
-400mV    21.07mA    12.09mA    29.9mA
-200mV    10.4mA     5.948mA    13.84mA
200mV     -9.115mA   -5.294mA   -12.98mA
600mV     -24.29mA   -13.56mA   -35.12mA
1V        -35.2mA    -18.69mA   -51.62mA
1.4V      -40.6mA    -20.72mA   -59.71mA
2.1V      -43.28mA   -21.83mA   -63.62mA
3.7V      -45.29mA   -22.8mA    -66.51mA
3.8V      -45.39mA   -30mA      -66.64mA
6.6V      -46mA      -30mA      -68.41mA
[GND_clamp]
|Voltage   I(typ)   I(min)   I(max)
-3.3V     -4.767A    -5.246A    -1.798A
-1.06V    -4.767A    -5.246A    -1.798A
-990mV    -327.3mA   -5.246A    -68.39mA
-920mV    -29.24mA   -722.7mA   -11.25mA
-850mV    -6.784mA   -104.5mA   -6.73mA
-780mV    -3.572mA   -17.39mA   -4.335mA
-500mV    -70.03uA   -187.2uA   -42.37uA
3.28V     73.94uA    88.61uA    51.47uA
[POWER_clamp]
|Voltage   I(typ)   I(min)   I(max)
-3.28V    30.09uA    10.99uA    56.63uA
-2.84V    27.27uA    10.11uA    50.92uA
-2.32V    25.55uA    9.609uA    47.36uA
-640mV    24.06uA    9.1uA      44.84uA
-600mV    22.76uA    8.366uA    43.37uA
-560mV    20.32uA    7.212uA    39.74uA
-520mV    16.86uA    5.676uA    34.15uA
-400mV    4.842uA    1.146uA    13.11uA
-360mV    2.185uA    478.4nA    7.29uA
-320mV    773nA      181.6nA    3.214uA
-240mV    60.58nA    0A         296.5nA
0V        0A         0A         0A
[Ramp]
| variable   typ   min   max
dV/dt_r  1.19406/27.00561n   0.63462/59.61128n   1.55520/13.56653n
dV/dt_f  1.27392/24.19049n   0.67098/53.41470n   1.57835/13.28057n
R_load = 50.000000
[Rising Waveform]
R_fixture= 50.000000
V_fixture= 3.300000
V_fixture_min= 2.700000
V_fixture_max= 3.600000
|time   V(typ)   V(min)   V(max)
0s        1.176V     1.571V     968.8mV
740.7ps   1.175V     1.571V     1.038V
1.041ns   1.172V     1.571V     3.082V
1.401ns   1.275V     1.571V     3.502V
1.522ns   1.565V     1.571V     3.527V
1.782ns   2.92V      1.57V      3.556V
2.142ns   3.233V     1.566V     3.576V
2.903ns   3.283V     1.682V     3.589V
3.744ns   3.292V     2.66V      3.594V
9.97ns    3.299V     2.698V     3.599V
[Rising Waveform]
R_fixture= 50.000000
V_fixture= 0.0
V_fixture_min= 0.0
V_fixture_max= 0.0
|time   V(typ)   V(min)   V(max)
0s        -502.2nV   -2.275uV   -342.1nV
8.008ns   -463.9uV   -171.2uV   86.72mV
15.52ns   88.93mV    -152.5uV   989mV
24.52ns   495.1mV    2.789mV    1.992V
30.03ns   798.2mV    20.47mV    2.325V
37.54ns   1.171V     61.7mV     2.505V
54.55ns   1.701V     240.8mV    2.58V
75.58ns   1.921V     513.9mV    2.591V
143.6ns   1.99V      980.7mV    2.592V
249.2ns   1.99V      1.06V      2.592V
[Falling Waveform]
R_fixture= 50.000000
V_fixture= 3.300000
V_fixture_min= 2.700000
V_fixture_max= 3.600000
|time   V(typ)   V(min)   V(max)
0s        3.299V     2.698V     3.599V
11.51ns   3.296V     2.695V     3.502V
19.52ns   3.229V     2.695V     2.586V
28.53ns   2.858V     2.695V     1.544V
33.53ns   2.585V     2.688V     1.188V
39.04ns   2.273V     2.666V     1.06V
56.06ns   1.482V     2.52V      987.4mV
72.57ns   1.279V     2.298V     974.5mV
125.6ns   1.185V     1.727V     969mV
249.2ns   1.176V     1.571V     968.8mV
[Falling Waveform]
R_fixture= 50.000000
V_fixture= 0.0
V_fixture_min= 0.0
V_fixture_max= 0.0
|time   V(typ)   V(min)   V(max)
0s        1.99V      1.06V      2.592V
961ps     1.99V      1.06V      2.539V
1.421ns   1.996V     1.06V      538.1mV
1.862ns   1.813V     1.06V      106mV
2.322ns   452.5mV    1.06V      45.81mV
2.803ns   71.88mV    1.065V     20.54mV
3.423ns   19.15mV    1.025V     7.559mV
4.104ns   7.235mV    281.5mV    4.015mV
4.705ns   3.797mV    34.18mV    2.782mV
9.97ns    -502.2nV   -2.275uV   -342.1nV
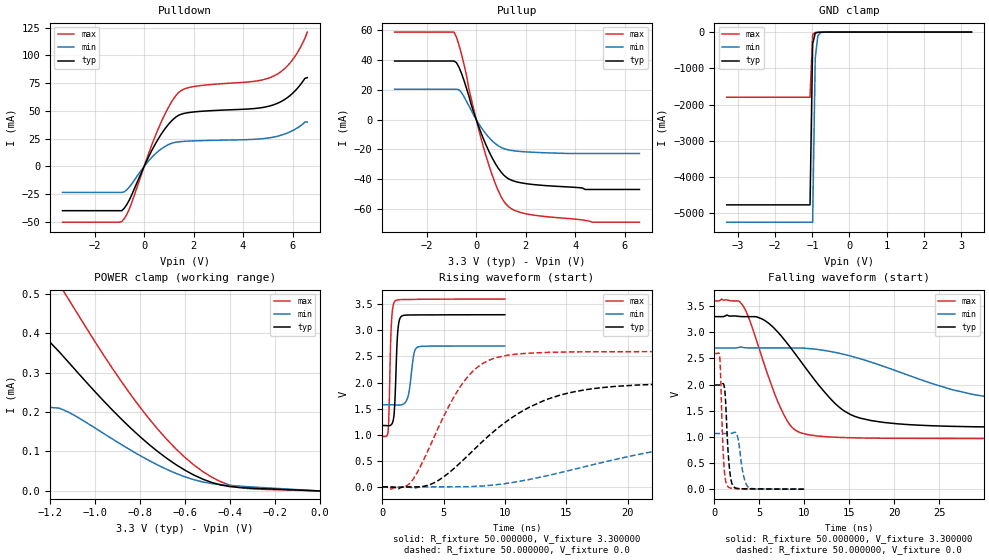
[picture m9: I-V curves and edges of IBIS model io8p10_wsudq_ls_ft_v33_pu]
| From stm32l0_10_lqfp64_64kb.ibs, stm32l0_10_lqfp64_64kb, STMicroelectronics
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|   Model io8p10_wsudq_ls_ft_v33_pu
[Model]  io8p10_wsudq_ls_ft_v33_pu
Model_type I/O
Polarity   Non-Inverting
Enable   Active-Low
Vinl =   0.990000V
Vinh =   2.310000V
Vmeas =  1.650000V
Cref =   50.000000pF
Rref =   100.000000M
Vref =   0.0V
C_comp   2.653200pF   2.620200pF   2.695100pF
[Temperature Range]   25.000000   0.125000k   -40.000000
[Pullup Reference]   3.300000V   2.700000V   3.600000V
[Pulldown Reference]   0.0V   0.0V   0.0V
[POWER Clamp Reference]   3.300000V   2.700000V   3.600000V
[GND Clamp Reference]   0.0V   0.0V   0.0V
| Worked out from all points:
|   slope of the pulldown table from 0 to 0.495 V, typ, clamps not added: 22.6 ohm
|   slope of the pullup table from 0 to 0.495 V, typ, clamps not added: 23.9 ohm
|   GND clamp passes 1 mA (typ) near -0.64 V on its own axis
|   POWER clamp passes 1 mA (typ) near -2.97 V on its own axis
|   rising waveform, R_fixture 50.000000, V_fixture 3.300000: 20-80 % time 213ps typ, 360ps min, 177ps max; typ from 1.18 V to 3.3 V
|   rising waveform, R_fixture 50.000000, V_fixture 0.0: 20-80 % time 6.54ns typ, 13.6ns min, 3.47ns max; typ from 0.001 V to 1.99 V
|   falling waveform, R_fixture 50.000000, V_fixture 3.300000: 20-80 % time 5.97ns typ, 12.6ns min, 3.28ns max; typ from 3.3 V to 1.18 V
|   falling waveform, R_fixture 50.000000, V_fixture 0.0: 20-80 % time 404ps typ, 569ps min, 326ps max; typ from 1.99 V to 0.001 V
[Pulldown]
|Voltage   I(typ)   I(min)   I(max)
-3.3V     -39.83mA   -23.37mA   -50.2mA
-900mV    -39.83mA   -23.37mA   -49.52mA
-600mV    -30.28mA   -18.59mA   -38.45mA
100mV     4.867mA    2.821mA    6.48mA
600mV     25.85mA    14.17mA    35.39mA
1V        38.33mA    19.81mA    53.88mA
1.4V      46.1mA     22.18mA    66.72mA
2V        49.07mA    23.02mA    71.93mA
4.4V      52.05mA    24.38mA    76.53mA
5.2V      55.25mA    26.3mA     81.02mA
6V        65.78mA    32.24mA    95.96mA
6.6V      80mA       40mA       121mA
[Pullup]
|Voltage   I(typ)   I(min)   I(max)
-3.3V     39.31mA    20.41mA    58.77mA
-900mV    39.31mA    20.41mA    58.77mA
-800mV    38.21mA    20.41mA    55.34mA
-600mV    31.27mA    18.2mA     44.2mA
0V        0A         25pA       0A
500mV     -20.88mA   -11.78mA   -30.07mA
900mV     -32.92mA   -17.72mA   -48.14mA
1.3V      -39.75mA   -20.4mA    -58.47mA
1.8V      -42.5mA    -21.48mA   -62.49mA
2.6V      -44.13mA   -22.23mA   -64.85mA
4.7V      -47mA      -22.8mA    -69mA
6.6V      -47mA      -22.8mA    -69mA
[GND_clamp]
|Voltage   I(typ)   I(min)   I(max)
-3.3V     -4.766A    -5.244A    -1.797A
-1.06V    -4.766A    -5.244A    -1.797A
-990mV    -326.7mA   -5.244A    -68.05mA
-920mV    -29.09mA   -722.2mA   -11.16mA
-850mV    -6.797mA   -104.4mA   -6.682mA
-780mV    -3.554mA   -17.44mA   -4.265mA
-500mV    -58.08uA   -169.3uA   -34.1uA
3.28V     0A         0A         0A
[POWER_clamp]
|Voltage   I(typ)   I(min)   I(max)
-3.28V    3.05A      226.6uA    3.724A
-2.96V    694.9uA    211.8uA    3.724A
-2.92V    479.6uA    211.8uA    509.1mA
-2.88V    432uA      211.8uA    70.08mA
-2.76V    412.8uA    211.8uA    794.1uA
-1.32V    411.6uA    211.8uA    593.3uA
-1.24V    395.5uA    211.8uA    578.2uA
-1.12V    327.2uA    200.2uA    487.6uA
-800mV    137.6uA    89.62uA    212.3uA
-560mV    40.27uA    28.42uA    65.81uA
-360mV    8.799uA    12.27uA    9.112uA
0V        0A         0A         0A
[Ramp]
| variable   typ   min   max
dV/dt_r  1.19492/6.52931n   0.63089/13.60559n   1.55547/3.46291n
dV/dt_f  1.27314/5.95725n   0.65472/12.52746n   1.57816/3.27066n
R_load = 50.000000
[Rising Waveform]
R_fixture= 50.000000
V_fixture= 3.300000
V_fixture_min= 2.700000
V_fixture_max= 3.600000
|time   V(typ)   V(min)   V(max)
0s        1.178V     1.575V     969.9mV
480.5ps   1.174V     1.576V     1.105V
740.7ps   1.198V     1.575V     3.153V
1.021ns   1.644V     1.573V     3.558V
1.241ns   2.935V     1.57V      3.584V
1.562ns   3.272V     1.574V     3.59V
2.102ns   3.294V     1.742V     3.592V
2.543ns   3.296V     2.514V     3.593V
2.883ns   3.296V     2.68V      3.595V
9.97ns    3.3V       2.7V       3.6V
[Rising Waveform]
R_fixture= 50.000000
V_fixture= 0.0
V_fixture_min= 0.0
V_fixture_max= 0.0
|time   V(typ)   V(min)   V(max)
0s        1.034mV    1.82mV     1.023mV
2.302ns   1.669mV    -6.846mV   87.79mV
4.204ns   78.58mV    3.713mV    952.7mV
6.406ns   476.4mV    4.627mV    1.942V
7.708ns   770.7mV    13.77mV    2.288V
9.309ns   1.11V      45.16mV    2.479V
13.41ns   1.678V     216.2mV    2.579V
18.62ns   1.92V      508.8mV    2.591V
31.53ns   1.99V      950mV      2.593V
49.85ns   1.993V     1.064V     2.593V
[Falling Waveform]
R_fixture= 50.000000
V_fixture= 3.300000
V_fixture_min= 2.700000
V_fixture_max= 3.600000
|time   V(typ)   V(min)   V(max)
0s        3.3V       2.7V       3.6V
3.203ns   3.3V       2.708V     3.5V
5.305ns   3.253V     2.702V     2.511V
7.407ns   2.934V     2.702V     1.535V
8.509ns   2.696V     2.701V     1.207V
9.71ns    2.42V      2.7V       1.073V
13.81ns   1.578V     2.601V     990.7mV
17.42ns   1.313V     2.429V     977.4mV
30.93ns   1.19V      1.751V     970.1mV
49.85ns   1.178V     1.575V     969.9mV
[Falling Waveform]
R_fixture= 50.000000
V_fixture= 0.0
V_fixture_min= 0.0
V_fixture_max= 0.0
|time   V(typ)   V(min)   V(max)
0s        1.993V     1.064V     2.593V
580.6ps   1.992V     1.064V     2.534V
1.041ns   1.998V     1.064V     493.3mV
1.221ns   1.733V     1.064V     186.6mV
1.461ns   876.5mV    1.064V     59.02mV
1.822ns   196.7mV    1.066V     20.94mV
2.262ns   30.97mV    1.089V     13.29mV
3.283ns   8.297mV    227.9mV    7.967mV
3.744ns   7.165mV    42.24mV    6.672mV
9.97ns    1.034mV    1.82mV     1.023mV
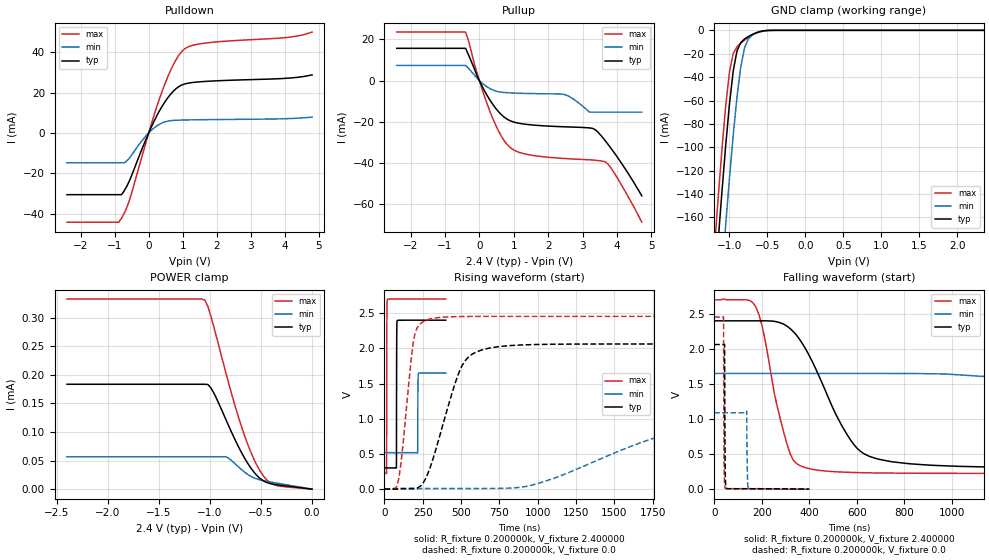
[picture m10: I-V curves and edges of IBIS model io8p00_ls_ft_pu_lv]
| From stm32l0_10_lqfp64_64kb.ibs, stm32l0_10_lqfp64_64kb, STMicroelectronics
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|   Model io8p00_ls_ft_pu_lv
[Model]  io8p00_ls_ft_pu_lv
Model_type I/O
Polarity   Non-Inverting
Enable   Active-Low
Vinl =   0.720000V
Vinh =   1.680000V
Vmeas =  1.200000V
Cref =   50.000000pF
Rref =   100.000000M
Vref =   0.0V
C_comp   4.521100pF   4.438000pF   4.578000pF
[Temperature Range]   25.000000   0.105000k   -40.000000
[Pullup Reference]   2.400000V   1.650000V   2.700000V
[Pulldown Reference]   0.0V   0.0V   0.0V
[POWER Clamp Reference]   2.400000V   1.650000V   2.700000V
[GND Clamp Reference]   0.0V   0.0V   0.0V
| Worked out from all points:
|   slope of the pulldown table from 0 to 0.36 V, typ, clamps not added: 29.5 ohm
|   slope of the pullup table from 0 to 0.36 V, typ, clamps not added: 33.2 ohm
|   GND clamp passes 1 mA (typ) near -0.59 V on its own axis
|   rising waveform, R_fixture 0.200000k, V_fixture 2.400000: 20-80 % time 1.15ns typ, 1.17ns min, 1.14ns max; typ from 0.302 V to 2.4 V
|   rising waveform, R_fixture 0.200000k, V_fixture 0.0: 20-80 % time 171ns typ, 825ns min, 67.2ns max; typ from 0.001 V to 2.06 V
|   falling waveform, R_fixture 0.200000k, V_fixture 2.400000: 20-80 % time 182ns typ, 739ns min, 90.9ns max; typ from 2.4 V to 0.302 V
|   falling waveform, R_fixture 0.200000k, V_fixture 0.0: 20-80 % time 1.78ns typ, 2.37ns min, 1.55ns max; typ from 2.06 V to 0.001 V
[Pulldown]
|Voltage   I(typ)   I(min)   I(max)
-2.4V     -30.64mA   -14.84mA   -44.29mA
-880mV    -30.64mA   -14.84mA   -44.29mA
-800mV    -30.64mA   -14.84mA   -42.37mA
-720mV    -28.74mA   -14.84mA   -39.91mA
-560mV    -23.52mA   -12.34mA   -33.09mA
0V        -765nA     -61nA      -2.526uA
400mV     13.38mA    4.998mA    20.91mA
720mV     20.62mA    6.178mA    33.69mA
1.04V     24.19mA    6.384mA    41.49mA
1.6V      25.46mA    6.544mA    44.42mA
4V        27.03mA    7.028mA    47.23mA
4.8V      28.76mA    7.817mA    49.99mA
[Pullup]
|Voltage   I(typ)   I(min)   I(max)
-2.4V     15.69mA    7.366mA    23.58mA
-400mV    15.69mA    7.366mA    23.58mA
-80mV     2.912mA    1.486mA    4.444mA
240mV     -7.653mA   -3.251mA   -12mA
560mV     -15.22mA   -5.43mA    -24.63mA
800mV     -18.73mA   -5.908mA   -31mA
1.28V     -21.13mA   -6.236mA   -35.54mA
2.48V     -22.51mA   -6.817mA   -37.93mA
3.2V      -23.05mA   -15.36mA   -38.57mA
3.36V     -23.83mA   -15.36mA   -38.77mA
3.76V     -31.49mA   -15.36mA   -41.07mA
4.72V     -56.1mA    -15.36mA   -68.92mA
[GND_clamp]
|Voltage   I(typ)   I(min)   I(max)
-2.4V     -1.379A    -1.445A    -1.35A
-1.2V     -225.9mA   -297.5mA   -189.2mA
-1.15V    -182mA     -253.1mA   -145.3mA
-1.1V     -139.6mA   -209.7mA   -103.5mA
-1.05V    -99.61mA   -167.6mA   -65.7mA
-1V       -63.67mA   -127.3mA   -35.89mA
-950mV    -35mA      -89.93mA   -19.87mA
-900mV    -17.67mA   -57.01mA   -14.12mA
-850mV    -10.49mA   -31.18mA   -11mA
-750mV    -5.288mA   -7.322mA   -5.997mA
-450mV    -33.57uA   -87.56uA   -14.35uA
2.35V     0A         0A         0A
[POWER_clamp]
|Voltage   I(typ)   I(min)   I(max)
-2.4V     183.5uA    56.67uA    332.6uA
-1.05V    183.5uA    56.67uA    330.7uA
-1.02V    183.2uA    56.67uA    319.4uA
-960mV    167.5uA    56.67uA    282.5uA
-840mV    120.2uA    56.67uA    200.6uA
-750mV    84.84uA    43.79uA    143.2uA
-690mV    63.63uA    34.11uA    108.8uA
-600mV    37.11uA    22.45uA    64.86uA
-510mV    18.78uA    16.35uA    32.08uA
-450mV    12.09uA    14.02uA    17.37uA
-360mV    8.168uA    11.12uA    6.844uA
0V        0A         0A         0A
[Ramp]
| variable   typ   min   max
dV/dt_r  0.63803/0.29999u   0.18817/0.81979u   1.01576/0.14374u
dV/dt_f  0.73962/0.32409u   0.19404/0.84893u   1.11751/0.16289u
R_load = 50.000000
[Rising Waveform]
R_fixture= 0.200000k
V_fixture= 2.400000
V_fixture_min= 1.650000
V_fixture_max= 2.700000
|time   V(typ)   V(min)   V(max)
0s        302.4mV    518.4mV    225.5mV
13.61ns   302.4mV    518.4mV    224.6mV
15.62ns   302.4mV    518.4mV    2.375V
19.22ns   302.4mV    518.4mV    2.695V
77.68ns   306.1mV    518.4mV    2.7V
79.68ns   2.096V     518.4mV    2.7V
82.88ns   2.393V     518.4mV    2.7V
215.8ns   2.4V       513.8mV    2.7V
222.2ns   2.4V       1.645V     2.7V
400ns     2.4V       1.65V      2.7V
[Rising Waveform]
R_fixture= 0.200000k
V_fixture= 0.0
V_fixture_min= 0.0
V_fixture_max= 0.0
|time   V(typ)   V(min)   V(max)
0s        1.23mV     2.239mV    705.2uV
93.43ns   10.52mV    2.239mV    149.5mV
200.2ns   12.5mV     2.239mV    2.223V
280.3ns   207.4mV    9.996mV    2.406V
373.7ns   860mV      9.996mV    2.441V
547.2ns   1.874V     10.03mV    2.453V
894.2ns   2.048V     29.53mV    2.454V
1.962us   2.062V     850.4mV    2.454V
2.776us   2.062V     1.054V     2.454V
13.33us   2.062V     1.09V      2.454V
[Falling Waveform]
R_fixture= 0.200000k
V_fixture= 2.400000
V_fixture_min= 1.650000
V_fixture_max= 2.700000
|time   V(typ)   V(min)   V(max)
0s        2.4V       1.65V      2.7V
173.5ns   2.4V       1.65V      2.609V
320.3ns   2.287V     1.65V      498.7mV
520.5ns   1.01V      1.65V      246.9mV
627.3ns   511mV      1.65V      235.1mV
827.5ns   361.3mV    1.649V     227.9mV
1.348us   309.2mV    1.507V     225.6mV
2.229us   302.6mV    728.3mV    225.5mV
3.043us   302.3mV    559.3mV    225.5mV
13.33us   302.4mV    518.4mV    225.5mV
[Falling Waveform]
R_fixture= 0.200000k
V_fixture= 0.0
V_fixture_min= 0.0
V_fixture_max= 0.0
|time   V(typ)   V(min)   V(max)
0s        2.062V     1.09V      2.454V
39.24ns   2.062V     1.09V      2.456V
41.64ns   2.062V     1.09V      385.3mV
43.64ns   2.064V     1.09V      69.4mV
46.05ns   369.7mV    1.09V      16.29mV
51.65ns   9.222mV    1.09V      9.323mV
136.5ns   6.329mV    1.115V     8.398mV
140.1ns   6.327mV    162.9mV    8.398mV
144.9ns   6.324mV    6.603mV    8.398mV
400ns     1.23mV     2.239mV    705.2uV
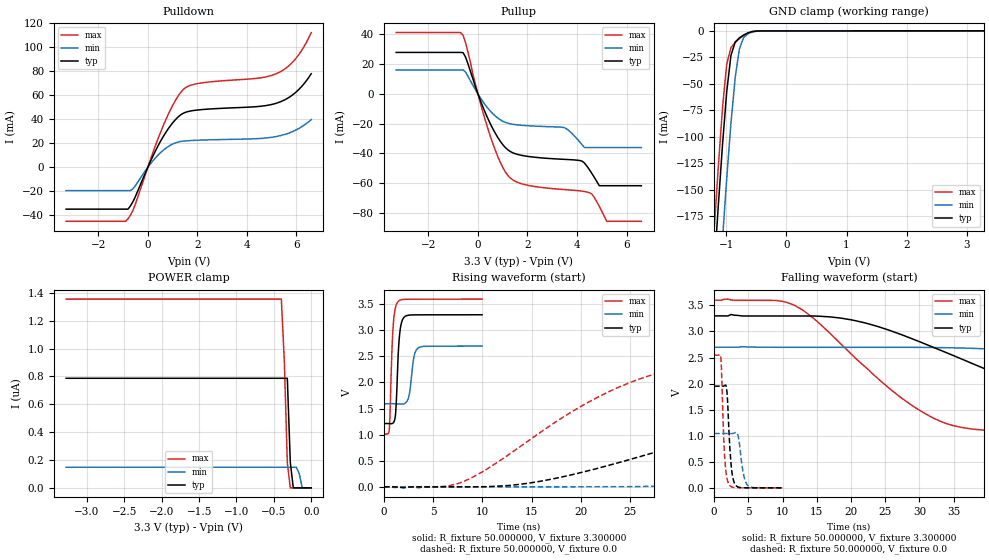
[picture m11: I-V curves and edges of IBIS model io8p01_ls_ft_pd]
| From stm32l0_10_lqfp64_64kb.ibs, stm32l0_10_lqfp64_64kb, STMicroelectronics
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|   Model io8p01_ls_ft_pd
[Model]  io8p01_ls_ft_pd
Model_type I/O
Polarity   Non-Inverting
Enable   Active-Low
Vinl =   0.990000V
Vinh =   2.310000V
Vmeas =  1.650000V
Cref =   50.000000pF
Rref =   100.000000M
Vref =   0.0V
C_comp   4.606100pF   4.563500pF   4.706200pF
[Temperature Range]   25.000000   0.125000k   -40.000000
[Pullup Reference]   3.300000V   2.700000V   3.600000V
[Pulldown Reference]   0.0V   0.0V   0.0V
[POWER Clamp Reference]   3.300000V   2.700000V   3.600000V
[GND Clamp Reference]   0.0V   0.0V   0.0V
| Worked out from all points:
|   slope of the pulldown table from 0 to 0.495 V, typ, clamps not added: 23.6 ohm
|   slope of the pullup table from 0 to 0.495 V, typ, clamps not added: 24.9 ohm
|   GND clamp passes 1 mA (typ) near -0.59 V on its own axis
|   rising waveform, R_fixture 50.000000, V_fixture 3.300000: 20-80 % time 316ps typ, 426ps min, 299ps max; typ from 1.21 V to 3.3 V
|   rising waveform, R_fixture 50.000000, V_fixture 0.0: 20-80 % time 27.1ns typ, 59.4ns min, 13.7ns max; typ from 0 V to 1.95 V
|   falling waveform, R_fixture 50.000000, V_fixture 3.300000: 20-80 % time 24.6ns typ, 53.5ns min, 13.5ns max; typ from 3.3 V to 1.21 V
|   falling waveform, R_fixture 50.000000, V_fixture 0.0: 20-80 % time 519ps typ, 682ps min, 457ps max; typ from 1.95 V to 0 V
[Pulldown]
|Voltage   I(typ)   I(min)   I(max)
-3.3V     -34.78mA   -19.34mA   -44.89mA
-900mV    -34.78mA   -19.34mA   -44.89mA
-800mV    -34.78mA   -19.34mA   -42.84mA
-600mV    -28.56mA   -17.8mA    -35.74mA
100mV     4.638mA    2.744mA    6.076mA
600mV     24.8mA     13.84mA    33.52mA
1V        36.92mA    19.39mA    51.35mA
1.4V      44.67mA    21.76mA    64.17mA
2V        47.7mA     22.58mA    69.7mA
5.2V      53.44mA    25.71mA    78.04mA
6V        62.89mA    31.28mA    91.14mA
6.6V      77.95mA    39.75mA    112.2mA
[Pullup]
|Voltage   I(typ)   I(min)   I(max)
-3.3V     27.88mA    16.14mA    41.22mA
-600mV    27.74mA    16.14mA    39.31mA
100mV     -4.445mA   -2.662mA   -6.169mA
500mV     -20.02mA   -11.5mA    -28.37mA
1V        -33.98mA   -18.31mA   -49.27mA
1.4V      -39.45mA   -20.34mA   -57.65mA
3.5V      -43.95mA   -22.7mA    -64.24mA
4.2V      -45.08mA   -33.97mA   -65.24mA
4.5V      -50.83mA   -36mA      -66.3mA
4.9V      -61.64mA   -36mA      -75.5mA
5.2V      -61.64mA   -36mA      -85.54mA
6.6V      -61.64mA   -36mA      -85.54mA
[GND_clamp]
|Voltage   I(typ)   I(min)   I(max)
-3.3V     -2.275A    -2.356A    -2.249A
-1.2V     -226mA     -318.7mA   -189.2mA
-1.13V    -164.9mA   -256.6mA   -128.3mA
-1.06V    -107.5mA   -196.5mA   -72.79mA
-990mV    -57.33mA   -139.4mA   -31.4mA
-920mV    -23.23mA   -87.33mA   -15.73mA
-850mV    -10.59mA   -44.46mA   -10.94mA
-780mV    -6.551mA   -17.26mA   -7.364mA
-710mV    -3.945mA   -6.365mA   -4.316mA
-640mV    -1.966mA   -2.806mA   -1.983mA
-360mV    -10.16uA   -28.12uA   -6.105uA
3.28V     73.92uA    88.6uA     51.45uA
[POWER_clamp]
|Voltage   I(typ)   I(min)   I(max)
-3.28V    786.7nA    148nA      1.355uA
-400mV    786.7nA    148nA      1.355uA
-360mV    786.7nA    148nA      908.2nA
-320mV    786.7nA    148nA      180.5nA
-280mV    182.6nA    148nA      0A
-240mV    0A         148nA      0A
-200mV    0A         148nA      0A
-160mV    0A         101.6nA    0A
-120mV    0A         0A         0A
0V        0A         0A         0A
[Ramp]
| variable   typ   min   max
dV/dt_r  1.17009/27.08942n   0.62399/59.39619n   1.52718/13.65234n
dV/dt_f  1.25142/24.62361n   0.65886/53.38265n   1.55262/13.51959n
R_load = 50.000000
[Rising Waveform]
R_fixture= 50.000000
V_fixture= 3.300000
V_fixture_min= 2.700000
V_fixture_max= 3.600000
|time   V(typ)   V(min)   V(max)
0s        1.213V     1.591V     1.012V
540.5ps   1.212V     1.591V     1.095V
920.9ps   1.222V     1.591V     3.034V
1.181ns   1.405V     1.591V     3.447V
1.381ns   2.232V     1.589V     3.539V
1.662ns   3.03V      1.586V     3.58V
2.162ns   3.27V      1.604V     3.594V
2.543ns   3.291V     1.745V     3.596V
3.423ns   3.297V     2.655V     3.597V
9.97ns    3.298V     2.698V     3.598V
[Rising Waveform]
R_fixture= 50.000000
V_fixture= 0.0
V_fixture_min= 0.0
V_fixture_max= 0.0
|time   V(typ)   V(min)   V(max)
0s        202uV      74.27uV    386.8uV
7.508ns   -452.6uV   -169uV     60.98mV
15.02ns   79.19mV    -153uV     928.7mV
24.52ns   499.5mV    2.933mV    1.963V
30.53ns   823.9mV    23.22mV    2.303V
38.54ns   1.201V     71.09mV    2.47V
54.55ns   1.67V      241.7mV    2.534V
77.58ns   1.891V     534.1mV    2.545V
137.6ns   1.949V     948.4mV    2.545V
249.2ns   1.95V      1.042V     2.545V
[Falling Waveform]
R_fixture= 50.000000
V_fixture= 3.300000
V_fixture_min= 2.700000
V_fixture_max= 3.600000
|time   V(typ)   V(min)   V(max)
0s        3.298V     2.698V     3.598V
11.51ns   3.296V     2.695V     3.515V
20.52ns   3.21V      2.695V     2.505V
29.53ns   2.828V     2.695V     1.529V
34.03ns   2.588V     2.688V     1.229V
40.04ns   2.257V     2.664V     1.098V
57.06ns   1.507V     2.516V     1.03V
75.08ns   1.307V     2.276V     1.017V
129.1ns   1.222V     1.734V     1.012V
249.2ns   1.213V     1.591V     1.012V
[Falling Waveform]
R_fixture= 50.000000
V_fixture= 0.0
V_fixture_min= 0.0
V_fixture_max= 0.0
|time   V(typ)   V(min)   V(max)
0s        1.95V      1.042V     2.545V
981ps     1.95V      1.042V     2.507V
1.542ns   1.962V     1.042V     611mV
1.862ns   1.868V     1.042V     201.7mV
2.142ns   1.172V     1.042V     77.33mV
2.563ns   350.1mV    1.042V     19.05mV
3.163ns   50.08mV    1.062V     3.83mV
4.344ns   1.86mV     236.5mV    1.421mV
4.925ns   894.8uV    45.22mV    1.139mV
9.97ns    202uV      74.27uV    386.8uV
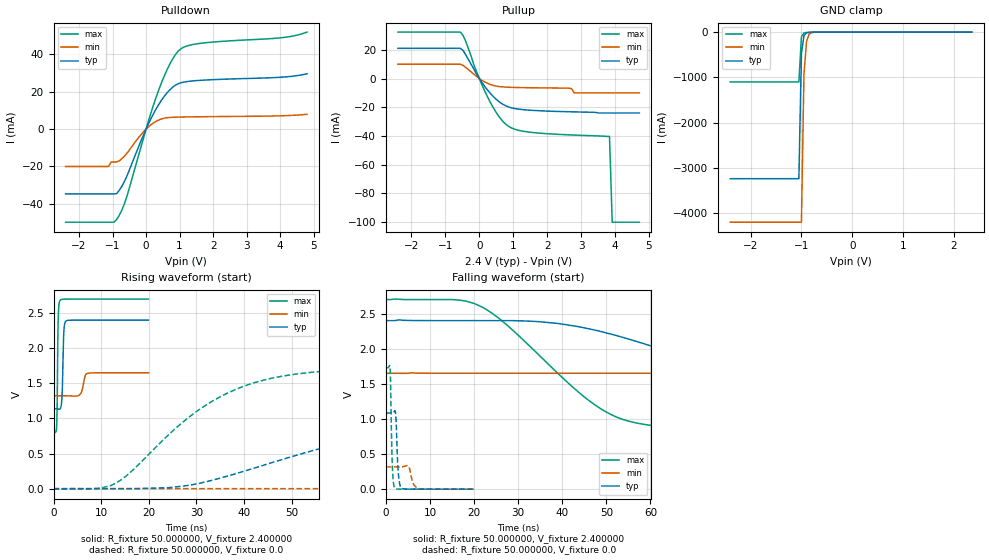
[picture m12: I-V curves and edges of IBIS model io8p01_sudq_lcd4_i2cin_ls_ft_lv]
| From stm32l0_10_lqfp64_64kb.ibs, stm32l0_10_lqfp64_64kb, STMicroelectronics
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|   Model io8p01_sudq_lcd4_i2cin_ls_ft_lv
[Model]  io8p01_sudq_lcd4_i2cin_ls_ft_lv
Model_type I/O
Polarity   Non-Inverting
Enable   Active-Low
Vinl =   0.720000V
Vinh =   1.680000V
Vmeas =  1.200000V
Cref =   50.000000pF
Rref =   100.000000M
Vref =   0.0V
C_comp   2.470900pF   2.435200pF   2.490500pF
[Temperature Range]   25.000000   0.105000k   -40.000000
[Pullup Reference]   2.400000V   1.650000V   2.700000V
[Pulldown Reference]   0.0V   0.0V   0.0V
[POWER Clamp Reference]   2.400000V   1.650000V   2.700000V
[GND Clamp Reference]   0.0V   0.0V   0.0V
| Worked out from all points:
|   slope of the pulldown table from 0 to 0.36 V, typ, clamps not added: 28.5 ohm
|   slope of the pullup table from 0 to 0.36 V, typ, clamps not added: 32.2 ohm
|   GND clamp passes 1 mA (typ) near -0.64 V on its own axis
|   rising waveform, R_fixture 50.000000, V_fixture 2.400000: 20-80 % time 282ps typ, 635ps min, 192ps max; typ from 1.14 V to 2.4 V
|   rising waveform, R_fixture 50.000000, V_fixture 0.0: 20-80 % time 39.5ns typ, 107ns min, 19.4ns max; typ from 0 V to 1.08 V
|   falling waveform, R_fixture 50.000000, V_fixture 2.400000: 20-80 % time 40.7ns typ, 106ns min, 20.1ns max; typ from 2.4 V to 1.14 V
|   falling waveform, R_fixture 50.000000, V_fixture 0.0: 20-80 % time 456ps typ, 830ps min, 358ps max; typ from 1.08 V to 0 V
[Pulldown]
|Voltage   I(typ)   I(min)   I(max)
-2.4V     -34.7mA    -20mA      -49.82mA
-1.12V    -34.7mA    -20mA      -49.82mA
-1.04V    -34.7mA    -17.6mA    -49.82mA
-880mV    -34.55mA   -17.6mA    -48.46mA
-560mV    -24.65mA   -12.68mA   -35.33mA
0V        224fA      0A         16fA
400mV     13.84mA    5.066mA    22.03mA
720mV     21.25mA    6.254mA    35.26mA
1.04V     24.82mA    6.464mA    43.03mA
1.6V      26.11mA    6.627mA    45.88mA
4V        27.76mA    7.125mA    48.87mA
4.8V      29.63mA    7.94mA     51.96mA
[Pullup]
|Voltage   I(typ)   I(min)   I(max)
-2.4V     21.07mA    9.995mA    32.35mA
-560mV    21.07mA    9.995mA    32.35mA
-400mV    16.53mA    7.728mA    25.89mA
-80mV     3.011mA    1.496mA    4.671mA
320mV     -10.16mA   -4.078mA   -16.34mA
640mV     -17.08mA   -5.718mA   -28.28mA
960mV     -20.45mA   -6.129mA   -34.49mA
1.76V     -22.39mA   -6.471mA   -37.97mA
2.8V      -23.2mA    -10mA      -39.35mA
3.84V     -24mA      -10mA      -40.3mA
3.92V     -24mA      -10mA      -100mA
4.72V     -24mA      -10mA      -100mA
[GND_clamp]
|Voltage   I(typ)   I(min)   I(max)
-2.4V     -3.237A    -4.197A    -1.1A
-1.05V    -3.237A    -4.197A    -1.1A
-1V       -475.5mA   -4.197A    -104.1mA
-950mV    -76.08mA   -935.1mA   -18.44mA
-900mV    -16.57mA   -212.6mA   -9.263mA
-850mV    -6.62mA    -50.88mA   -6.764mA
-800mV    -4.092mA   -13.84mA   -4.994mA
-650mV    -1.07mA    -1.21mA    -1.175mA
2.35V     0A         0A         0A
[POWER_clamp]
|Voltage   I(typ)   I(min)   I(max)
-2.4V     0A         0A         0A
0V        0A         0A         0A
[Ramp]
| variable   typ   min   max
dV/dt_r  0.65070/39.48266n   0.18972/0.10637u   1.03800/19.37271n
dV/dt_f  0.75690/40.66445n   0.19476/0.10556u   1.13815/20.04001n
R_load = 50.000000
[Rising Waveform]
R_fixture= 50.000000
V_fixture= 2.400000
V_fixture_min= 1.650000
V_fixture_max= 2.700000
|time   V(typ)   V(min)   V(max)
0s        1.139V     1.322V     802.9mV
680.7ps   1.138V     1.322V     922.7mV
961ps     1.134V     1.322V     2.354V
1.361ns   1.135V     1.322V     2.68V
1.802ns   1.342V     1.322V     2.697V
2.202ns   2.275V     1.322V     2.698V
2.563ns   2.383V     1.322V     2.699V
5.526ns   2.4V       1.339V     2.7V
7.247ns   2.4V       1.643V     2.7V
19.94ns   2.4V       1.65V      2.7V
[Rising Waveform]
R_fixture= 50.000000
V_fixture= 0.0
V_fixture_min= 0.0
V_fixture_max= 0.0
|time   V(typ)   V(min)   V(max)
0s        8.058uV    -3.87uV    -11.73uV
13.01ns   -210.8uV   -46.35uV   76.82mV
29.03ns   54.63mV    -46uV      1.049V
39.04ns   229.1mV    -46.08uV   1.435V
48.05ns   416.1mV    -39.14uV   1.602V
61.06ns   656.5mV    21.18uV    1.692V
91.09ns   962.4mV    2.037mV    1.727V
134.1ns   1.069V     62.91mV    1.73V
254.3ns   1.085V     267.5mV    1.73V
498.5ns   1.085V     316.6mV    1.73V
[Falling Waveform]
R_fixture= 50.000000
V_fixture= 2.400000
V_fixture_min= 1.650000
V_fixture_max= 2.700000
|time   V(typ)   V(min)   V(max)
0s        2.4V       1.65V      2.7V
20.02ns   2.4V       1.65V      2.644V
26.03ns   2.4V       1.65V      2.412V
49.05ns   2.24V      1.65V      1.132V
56.06ns   2.118V     1.65V      952.6mV
68.07ns   1.871V     1.65V      863.4mV
98.1ns    1.362V     1.65V      814.9mV
138.1ns   1.195V     1.633V     804.6mV
286.3ns   1.139V     1.381V     802.9mV
498.5ns   1.139V     1.322V     802.9mV
[Falling Waveform]
R_fixture= 50.000000
V_fixture= 0.0
V_fixture_min= 0.0
V_fixture_max= 0.0
|time   V(typ)   V(min)   V(max)
0s        1.085V     316.6mV    1.73V
961ps     1.085V     316.6mV    1.716V
1.481ns   1.084V     316.6mV    323.5mV
2.042ns   1.118V     316.6mV    18.08mV
2.282ns   1.013V     316.6mV    5.957mV
2.803ns   248.7mV    316.4mV    1.179mV
3.403ns   21.39mV    316.1mV    658.6uV
5.045ns   371.5uV    331mV      235.8uV
7.528ns   90.69uV    7.689mV    40.69uV
19.94ns   8.058uV    -3.87uV    -11.73uV
